VERSION 5.7 ;
BUSBITCHARS "[]" ;
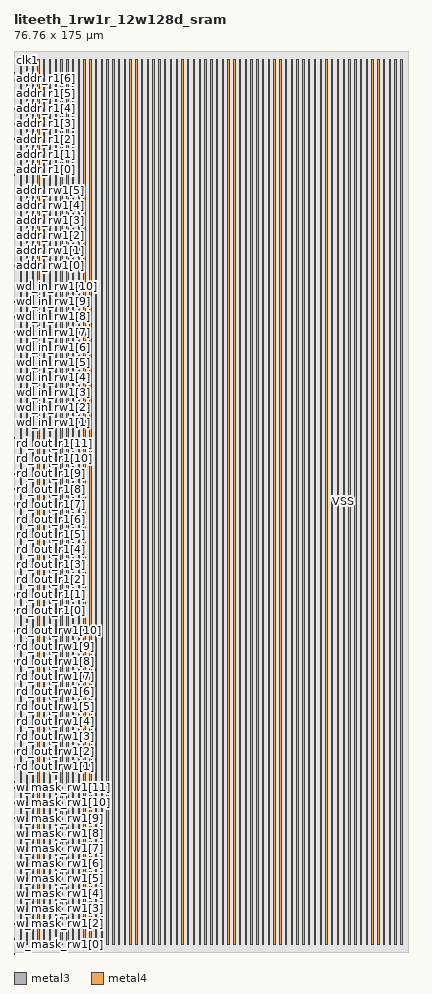
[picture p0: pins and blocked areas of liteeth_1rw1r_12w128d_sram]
MACRO liteeth_1rw1r_12w128d_sram
  FOREIGN liteeth_1rw1r_12w128d_sram 0 0 ;
  SYMMETRY X Y R90 ;
  SIZE 76.760 BY 175.000 ;
  CLASS BLOCK ;
  PIN w_mask_rw1[0]
    DIRECTION INPUT ;
    USE SIGNAL ;
    SHAPE ABUTMENT ;
    PORT
      LAYER metal3 ;
      RECT 0.000 -0.455 0.070 -0.385 ;
    END
  END w_mask_rw1[0]
  PIN w_mask_rw1[1]
    DIRECTION INPUT ;
    USE SIGNAL ;
    SHAPE ABUTMENT ;
    PORT
      LAYER metal3 ;
      RECT 0.000 2.485 0.070 2.555 ;
    END
  END w_mask_rw1[1]
  PIN w_mask_rw1[2]
    DIRECTION INPUT ;
    USE SIGNAL ;
    SHAPE ABUTMENT ;
    PORT
      LAYER metal3 ;
      RECT 0.000 5.425 0.070 5.495 ;
    END
  END w_mask_rw1[2]
  PIN w_mask_rw1[3]
    DIRECTION INPUT ;
    USE SIGNAL ;
    SHAPE ABUTMENT ;
    PORT
      LAYER metal3 ;
      RECT 0.000 8.365 0.070 8.435 ;
    END
  END w_mask_rw1[3]
  PIN w_mask_rw1[4]
    DIRECTION INPUT ;
    USE SIGNAL ;
    SHAPE ABUTMENT ;
    PORT
      LAYER metal3 ;
      RECT 0.000 11.305 0.070 11.375 ;
    END
  END w_mask_rw1[4]
  PIN w_mask_rw1[5]
    DIRECTION INPUT ;
    USE SIGNAL ;
    SHAPE ABUTMENT ;
    PORT
      LAYER metal3 ;
      RECT 0.000 14.245 0.070 14.315 ;
    END
  END w_mask_rw1[5]
  PIN w_mask_rw1[6]
    DIRECTION INPUT ;
    USE SIGNAL ;
    SHAPE ABUTMENT ;
    PORT
      LAYER metal3 ;
      RECT 0.000 17.185 0.070 17.255 ;
    END
  END w_mask_rw1[6]
  PIN w_mask_rw1[7]
    DIRECTION INPUT ;
    USE SIGNAL ;
    SHAPE ABUTMENT ;
    PORT
      LAYER metal3 ;
      RECT 0.000 20.125 0.070 20.195 ;
    END
  END w_mask_rw1[7]
  PIN w_mask_rw1[8]
    DIRECTION INPUT ;
    USE SIGNAL ;
    SHAPE ABUTMENT ;
    PORT
      LAYER metal3 ;
      RECT 0.000 23.065 0.070 23.135 ;
    END
  END w_mask_rw1[8]
  PIN w_mask_rw1[9]
    DIRECTION INPUT ;
    USE SIGNAL ;
    SHAPE ABUTMENT ;
    PORT
      LAYER metal3 ;
      RECT 0.000 26.005 0.070 26.075 ;
    END
  END w_mask_rw1[9]
  PIN w_mask_rw1[10]
    DIRECTION INPUT ;
    USE SIGNAL ;
    SHAPE ABUTMENT ;
    PORT
      LAYER metal3 ;
      RECT 0.000 28.945 0.070 29.015 ;
    END
  END w_mask_rw1[10]
  PIN w_mask_rw1[11]
    DIRECTION INPUT ;
    USE SIGNAL ;
    SHAPE ABUTMENT ;
    PORT
      LAYER metal3 ;
      RECT 0.000 31.885 0.070 31.955 ;
    END
  END w_mask_rw1[11]
  PIN rd_out_rw1[0]
    DIRECTION OUTPUT ;
    USE SIGNAL ;
    SHAPE ABUTMENT ;
    PORT
      LAYER metal3 ;
      RECT 0.000 33.005 0.070 33.075 ;
    END
  END rd_out_rw1[0]
  PIN rd_out_rw1[1]
    DIRECTION OUTPUT ;
    USE SIGNAL ;
    SHAPE ABUTMENT ;
    PORT
      LAYER metal3 ;
      RECT 0.000 35.945 0.070 36.015 ;
    END
  END rd_out_rw1[1]
  PIN rd_out_rw1[2]
    DIRECTION OUTPUT ;
    USE SIGNAL ;
    SHAPE ABUTMENT ;
    PORT
      LAYER metal3 ;
      RECT 0.000 38.885 0.070 38.955 ;
    END
  END rd_out_rw1[2]
  PIN rd_out_rw1[3]
    DIRECTION OUTPUT ;
    USE SIGNAL ;
    SHAPE ABUTMENT ;
    PORT
      LAYER metal3 ;
      RECT 0.000 41.825 0.070 41.895 ;
    END
  END rd_out_rw1[3]
  PIN rd_out_rw1[4]
    DIRECTION OUTPUT ;
    USE SIGNAL ;
    SHAPE ABUTMENT ;
    PORT
      LAYER metal3 ;
      RECT 0.000 44.765 0.070 44.835 ;
    END
  END rd_out_rw1[4]
  PIN rd_out_rw1[5]
    DIRECTION OUTPUT ;
    USE SIGNAL ;
    SHAPE ABUTMENT ;
    PORT
      LAYER metal3 ;
      RECT 0.000 47.705 0.070 47.775 ;
    END
  END rd_out_rw1[5]
  PIN rd_out_rw1[6]
    DIRECTION OUTPUT ;
    USE SIGNAL ;
    SHAPE ABUTMENT ;
    PORT
      LAYER metal3 ;
      RECT 0.000 50.645 0.070 50.715 ;
    END
  END rd_out_rw1[6]
  PIN rd_out_rw1[7]
    DIRECTION OUTPUT ;
    USE SIGNAL ;
    SHAPE ABUTMENT ;
    PORT
      LAYER metal3 ;
      RECT 0.000 53.585 0.070 53.655 ;
    END
  END rd_out_rw1[7]
  PIN rd_out_rw1[8]
    DIRECTION OUTPUT ;
    USE SIGNAL ;
    SHAPE ABUTMENT ;
    PORT
      LAYER metal3 ;
      RECT 0.000 56.525 0.070 56.595 ;
    END
  END rd_out_rw1[8]
  PIN rd_out_rw1[9]
    DIRECTION OUTPUT ;
    USE SIGNAL ;
    SHAPE ABUTMENT ;
    PORT
      LAYER metal3 ;
      RECT 0.000 59.465 0.070 59.535 ;
    END
  END rd_out_rw1[9]
  PIN rd_out_rw1[10]
    DIRECTION OUTPUT ;
    USE SIGNAL ;
    SHAPE ABUTMENT ;
    PORT
      LAYER metal3 ;
      RECT 0.000 62.405 0.070 62.475 ;
    END
  END rd_out_rw1[10]
  PIN rd_out_rw1[11]
    DIRECTION OUTPUT ;
    USE SIGNAL ;
    SHAPE ABUTMENT ;
    PORT
      LAYER metal3 ;
      RECT 0.000 65.345 0.070 65.415 ;
    END
  END rd_out_rw1[11]
  PIN rd_out_r1[0]
    DIRECTION OUTPUT ;
    USE SIGNAL ;
    SHAPE ABUTMENT ;
    PORT
      LAYER metal3 ;
      RECT 0.000 66.465 0.070 66.535 ;
    END
  END rd_out_r1[0]
  PIN rd_out_r1[1]
    DIRECTION OUTPUT ;
    USE SIGNAL ;
    SHAPE ABUTMENT ;
    PORT
      LAYER metal3 ;
      RECT 0.000 69.405 0.070 69.475 ;
    END
  END rd_out_r1[1]
  PIN rd_out_r1[2]
    DIRECTION OUTPUT ;
    USE SIGNAL ;
    SHAPE ABUTMENT ;
    PORT
      LAYER metal3 ;
      RECT 0.000 72.345 0.070 72.415 ;
    END
  END rd_out_r1[2]
  PIN rd_out_r1[3]
    DIRECTION OUTPUT ;
    USE SIGNAL ;
    SHAPE ABUTMENT ;
    PORT
      LAYER metal3 ;
      RECT 0.000 75.285 0.070 75.355 ;
    END
  END rd_out_r1[3]
  PIN rd_out_r1[4]
    DIRECTION OUTPUT ;
    USE SIGNAL ;
    SHAPE ABUTMENT ;
    PORT
      LAYER metal3 ;
      RECT 0.000 78.225 0.070 78.295 ;
    END
  END rd_out_r1[4]
  PIN rd_out_r1[5]
    DIRECTION OUTPUT ;
    USE SIGNAL ;
    SHAPE ABUTMENT ;
    PORT
      LAYER metal3 ;
      RECT 0.000 81.165 0.070 81.235 ;
    END
  END rd_out_r1[5]
  PIN rd_out_r1[6]
    DIRECTION OUTPUT ;
    USE SIGNAL ;
    SHAPE ABUTMENT ;
    PORT
      LAYER metal3 ;
      RECT 0.000 84.105 0.070 84.175 ;
    END
  END rd_out_r1[6]
  PIN rd_out_r1[7]
    DIRECTION OUTPUT ;
    USE SIGNAL ;
    SHAPE ABUTMENT ;
    PORT
      LAYER metal3 ;
      RECT 0.000 87.045 0.070 87.115 ;
    END
  END rd_out_r1[7]
  PIN rd_out_r1[8]
    DIRECTION OUTPUT ;
    USE SIGNAL ;
    SHAPE ABUTMENT ;
    PORT
      LAYER metal3 ;
      RECT 0.000 89.985 0.070 90.055 ;
    END
  END rd_out_r1[8]
  PIN rd_out_r1[9]
    DIRECTION OUTPUT ;
    USE SIGNAL ;
    SHAPE ABUTMENT ;
    PORT
      LAYER metal3 ;
      RECT 0.000 92.925 0.070 92.995 ;
    END
  END rd_out_r1[9]
  PIN rd_out_r1[10]
    DIRECTION OUTPUT ;
    USE SIGNAL ;
    SHAPE ABUTMENT ;
    PORT
      LAYER metal3 ;
      RECT 0.000 95.865 0.070 95.935 ;
    END
  END rd_out_r1[10]
  PIN rd_out_r1[11]
    DIRECTION OUTPUT ;
    USE SIGNAL ;
    SHAPE ABUTMENT ;
    PORT
      LAYER metal3 ;
      RECT 0.000 98.805 0.070 98.875 ;
    END
  END rd_out_r1[11]
  PIN wd_in_rw1[0]
    DIRECTION INPUT ;
    USE SIGNAL ;
    SHAPE ABUTMENT ;
    PORT
      LAYER metal3 ;
      RECT 0.000 99.925 0.070 99.995 ;
    END
  END wd_in_rw1[0]
  PIN wd_in_rw1[1]
    DIRECTION INPUT ;
    USE SIGNAL ;
    SHAPE ABUTMENT ;
    PORT
      LAYER metal3 ;
      RECT 0.000 102.865 0.070 102.935 ;
    END
  END wd_in_rw1[1]
  PIN wd_in_rw1[2]
    DIRECTION INPUT ;
    USE SIGNAL ;
    SHAPE ABUTMENT ;
    PORT
      LAYER metal3 ;
      RECT 0.000 105.805 0.070 105.875 ;
    END
  END wd_in_rw1[2]
  PIN wd_in_rw1[3]
    DIRECTION INPUT ;
    USE SIGNAL ;
    SHAPE ABUTMENT ;
    PORT
      LAYER metal3 ;
      RECT 0.000 108.745 0.070 108.815 ;
    END
  END wd_in_rw1[3]
  PIN wd_in_rw1[4]
    DIRECTION INPUT ;
    USE SIGNAL ;
    SHAPE ABUTMENT ;
    PORT
      LAYER metal3 ;
      RECT 0.000 111.685 0.070 111.755 ;
    END
  END wd_in_rw1[4]
  PIN wd_in_rw1[5]
    DIRECTION INPUT ;
    USE SIGNAL ;
    SHAPE ABUTMENT ;
    PORT
      LAYER metal3 ;
      RECT 0.000 114.625 0.070 114.695 ;
    END
  END wd_in_rw1[5]
  PIN wd_in_rw1[6]
    DIRECTION INPUT ;
    USE SIGNAL ;
    SHAPE ABUTMENT ;
    PORT
      LAYER metal3 ;
      RECT 0.000 117.565 0.070 117.635 ;
    END
  END wd_in_rw1[6]
  PIN wd_in_rw1[7]
    DIRECTION INPUT ;
    USE SIGNAL ;
    SHAPE ABUTMENT ;
    PORT
      LAYER metal3 ;
      RECT 0.000 120.505 0.070 120.575 ;
    END
  END wd_in_rw1[7]
  PIN wd_in_rw1[8]
    DIRECTION INPUT ;
    USE SIGNAL ;
    SHAPE ABUTMENT ;
    PORT
      LAYER metal3 ;
      RECT 0.000 123.445 0.070 123.515 ;
    END
  END wd_in_rw1[8]
  PIN wd_in_rw1[9]
    DIRECTION INPUT ;
    USE SIGNAL ;
    SHAPE ABUTMENT ;
    PORT
      LAYER metal3 ;
      RECT 0.000 126.385 0.070 126.455 ;
    END
  END wd_in_rw1[9]
  PIN wd_in_rw1[10]
    DIRECTION INPUT ;
    USE SIGNAL ;
    SHAPE ABUTMENT ;
    PORT
      LAYER metal3 ;
      RECT 0.000 129.325 0.070 129.395 ;
    END
  END wd_in_rw1[10]
  PIN wd_in_rw1[11]
    DIRECTION INPUT ;
    USE SIGNAL ;
    SHAPE ABUTMENT ;
    PORT
      LAYER metal3 ;
      RECT 0.000 132.265 0.070 132.335 ;
    END
  END wd_in_rw1[11]
  PIN addr_rw1[0]
    DIRECTION INPUT ;
    USE SIGNAL ;
    SHAPE ABUTMENT ;
    PORT
      LAYER metal3 ;
      RECT 0.000 133.385 0.070 133.455 ;
    END
  END addr_rw1[0]
  PIN addr_rw1[1]
    DIRECTION INPUT ;
    USE SIGNAL ;
    SHAPE ABUTMENT ;
    PORT
      LAYER metal3 ;
      RECT 0.000 136.325 0.070 136.395 ;
    END
  END addr_rw1[1]
  PIN addr_rw1[2]
    DIRECTION INPUT ;
    USE SIGNAL ;
    SHAPE ABUTMENT ;
    PORT
      LAYER metal3 ;
      RECT 0.000 139.265 0.070 139.335 ;
    END
  END addr_rw1[2]
  PIN addr_rw1[3]
    DIRECTION INPUT ;
    USE SIGNAL ;
    SHAPE ABUTMENT ;
    PORT
      LAYER metal3 ;
      RECT 0.000 142.205 0.070 142.275 ;
    END
  END addr_rw1[3]
  PIN addr_rw1[4]
    DIRECTION INPUT ;
    USE SIGNAL ;
    SHAPE ABUTMENT ;
    PORT
      LAYER metal3 ;
      RECT 0.000 145.145 0.070 145.215 ;
    END
  END addr_rw1[4]
  PIN addr_rw1[5]
    DIRECTION INPUT ;
    USE SIGNAL ;
    SHAPE ABUTMENT ;
    PORT
      LAYER metal3 ;
      RECT 0.000 148.085 0.070 148.155 ;
    END
  END addr_rw1[5]
  PIN addr_rw1[6]
    DIRECTION INPUT ;
    USE SIGNAL ;
    SHAPE ABUTMENT ;
    PORT
      LAYER metal3 ;
      RECT 0.000 151.025 0.070 151.095 ;
    END
  END addr_rw1[6]
  PIN addr_r1[0]
    DIRECTION INPUT ;
    USE SIGNAL ;
    SHAPE ABUTMENT ;
    PORT
      LAYER metal3 ;
      RECT 0.000 152.145 0.070 152.215 ;
    END
  END addr_r1[0]
  PIN addr_r1[1]
    DIRECTION INPUT ;
    USE SIGNAL ;
    SHAPE ABUTMENT ;
    PORT
      LAYER metal3 ;
      RECT 0.000 155.085 0.070 155.155 ;
    END
  END addr_r1[1]
  PIN addr_r1[2]
    DIRECTION INPUT ;
    USE SIGNAL ;
    SHAPE ABUTMENT ;
    PORT
      LAYER metal3 ;
      RECT 0.000 158.025 0.070 158.095 ;
    END
  END addr_r1[2]
  PIN addr_r1[3]
    DIRECTION INPUT ;
    USE SIGNAL ;
    SHAPE ABUTMENT ;
    PORT
      LAYER metal3 ;
      RECT 0.000 160.965 0.070 161.035 ;
    END
  END addr_r1[3]
  PIN addr_r1[4]
    DIRECTION INPUT ;
    USE SIGNAL ;
    SHAPE ABUTMENT ;
    PORT
      LAYER metal3 ;
      RECT 0.000 163.905 0.070 163.975 ;
    END
  END addr_r1[4]
  PIN addr_r1[5]
    DIRECTION INPUT ;
    USE SIGNAL ;
    SHAPE ABUTMENT ;
    PORT
      LAYER metal3 ;
      RECT 0.000 166.845 0.070 166.915 ;
    END
  END addr_r1[5]
  PIN addr_r1[6]
    DIRECTION INPUT ;
    USE SIGNAL ;
    SHAPE ABUTMENT ;
    PORT
      LAYER metal3 ;
      RECT 0.000 169.785 0.070 169.855 ;
    END
  END addr_r1[6]
  PIN we_in_rw1
    DIRECTION INPUT ;
    USE SIGNAL ;
    SHAPE ABUTMENT ;
    PORT
      LAYER metal3 ;
      RECT 0.000 170.905 0.070 170.975 ;
    END
  END we_in_rw1
  PIN ce_rw1
    DIRECTION INPUT ;
    USE SIGNAL ;
    SHAPE ABUTMENT ;
    PORT
      LAYER metal3 ;
      RECT 0.000 170.205 0.070 170.275 ;
    END
  END ce_rw1
  PIN ce_r1
    DIRECTION INPUT ;
    USE SIGNAL ;
    SHAPE ABUTMENT ;
    PORT
      LAYER metal3 ;
      RECT 0.000 169.505 0.070 169.575 ;
    END
  END ce_r1
  PIN clk0
    DIRECTION INPUT ;
    USE SIGNAL ;
    SHAPE ABUTMENT ;
    PORT
      LAYER metal3 ;
      RECT 0.000 170.625 0.070 170.695 ;
    END
  END clk0
  PIN clk1
    DIRECTION INPUT ;
    USE SIGNAL ;
    SHAPE ABUTMENT ;
    PORT
      LAYER metal3 ;
      RECT 0.000 173.565 0.070 173.635 ;
    END
  END clk1
  PIN VSS
    DIRECTION INOUT ;
    USE GROUND ;
    PORT
      LAYER metal4 ;
      RECT 1.260 1.400 1.540 173.600 ;
      RECT 3.500 1.400 3.780 173.600 ;
      RECT 5.740 1.400 6.020 173.600 ;
      RECT 7.980 1.400 8.260 173.600 ;
      RECT 10.220 1.400 10.500 173.600 ;
      RECT 12.460 1.400 12.740 173.600 ;
      RECT 14.700 1.400 14.980 173.600 ;
      RECT 16.940 1.400 17.220 173.600 ;
      RECT 19.180 1.400 19.460 173.600 ;
      RECT 21.420 1.400 21.700 173.600 ;
      RECT 23.660 1.400 23.940 173.600 ;
      RECT 25.900 1.400 26.180 173.600 ;
      RECT 28.140 1.400 28.420 173.600 ;
      RECT 30.380 1.400 30.660 173.600 ;
      RECT 32.620 1.400 32.900 173.600 ;
      RECT 34.860 1.400 35.140 173.600 ;
      RECT 37.100 1.400 37.380 173.600 ;
      RECT 39.340 1.400 39.620 173.600 ;
      RECT 41.580 1.400 41.860 173.600 ;
      RECT 43.820 1.400 44.100 173.600 ;
      RECT 46.060 1.400 46.340 173.600 ;
      RECT 48.300 1.400 48.580 173.600 ;
      RECT 50.540 1.400 50.820 173.600 ;
      RECT 52.780 1.400 53.060 173.600 ;
      RECT 55.020 1.400 55.300 173.600 ;
      RECT 57.260 1.400 57.540 173.600 ;
      RECT 59.500 1.400 59.780 173.600 ;
      RECT 61.740 1.400 62.020 173.600 ;
      RECT 63.980 1.400 64.260 173.600 ;
      RECT 66.220 1.400 66.500 173.600 ;
      RECT 68.460 1.400 68.740 173.600 ;
      RECT 70.700 1.400 70.980 173.600 ;
      RECT 72.940 1.400 73.220 173.600 ;
      RECT 75.180 1.400 75.460 173.600 ;
    END
  END VSS
  PIN VDD
    DIRECTION INOUT ;
    USE POWER ;
    PORT
      LAYER metal4 ;
      RECT 2.380 1.400 2.660 173.600 ;
      RECT 4.620 1.400 4.900 173.600 ;
      RECT 6.860 1.400 7.140 173.600 ;
      RECT 9.100 1.400 9.380 173.600 ;
      RECT 11.340 1.400 11.620 173.600 ;
      RECT 13.580 1.400 13.860 173.600 ;
      RECT 15.820 1.400 16.100 173.600 ;
      RECT 18.060 1.400 18.340 173.600 ;
      RECT 20.300 1.400 20.580 173.600 ;
      RECT 22.540 1.400 22.820 173.600 ;
      RECT 24.780 1.400 25.060 173.600 ;
      RECT 27.020 1.400 27.300 173.600 ;
      RECT 29.260 1.400 29.540 173.600 ;
      RECT 31.500 1.400 31.780 173.600 ;
      RECT 33.740 1.400 34.020 173.600 ;
      RECT 35.980 1.400 36.260 173.600 ;
      RECT 38.220 1.400 38.500 173.600 ;
      RECT 40.460 1.400 40.740 173.600 ;
      RECT 42.700 1.400 42.980 173.600 ;
      RECT 44.940 1.400 45.220 173.600 ;
      RECT 47.180 1.400 47.460 173.600 ;
      RECT 49.420 1.400 49.700 173.600 ;
      RECT 51.660 1.400 51.940 173.600 ;
      RECT 53.900 1.400 54.180 173.600 ;
      RECT 56.140 1.400 56.420 173.600 ;
      RECT 58.380 1.400 58.660 173.600 ;
      RECT 60.620 1.400 60.900 173.600 ;
      RECT 62.860 1.400 63.140 173.600 ;
      RECT 65.100 1.400 65.380 173.600 ;
      RECT 67.340 1.400 67.620 173.600 ;
      RECT 69.580 1.400 69.860 173.600 ;
      RECT 71.820 1.400 72.100 173.600 ;
      RECT 74.060 1.400 74.340 173.600 ;
    END
  END VDD
  OBS
    LAYER metal1 ;
    RECT 0 0 76.760 175.000 ;
    LAYER metal2 ;
    RECT 0 0 76.760 175.000 ;
    LAYER metal3 ;
    RECT 0.070 0 76.760 175.000 ;
    RECT 0 0.000 0.070 1.365 ;
    RECT 0 1.435 0.070 4.305 ;
    RECT 0 4.375 0.070 7.245 ;
    RECT 0 7.315 0.070 10.185 ;
    RECT 0 10.255 0.070 13.125 ;
    RECT 0 13.195 0.070 16.065 ;
    RECT 0 16.135 0.070 19.005 ;
    RECT 0 19.075 0.070 21.945 ;
    RECT 0 22.015 0.070 24.885 ;
    RECT 0 24.955 0.070 27.825 ;
    RECT 0 27.895 0.070 30.765 ;
    RECT 0 30.835 0.070 33.705 ;
    RECT 0 33.775 0.070 34.825 ;
    RECT 0 34.895 0.070 37.765 ;
    RECT 0 37.835 0.070 40.705 ;
    RECT 0 40.775 0.070 43.645 ;
    RECT 0 43.715 0.070 46.585 ;
    RECT 0 46.655 0.070 49.525 ;
    RECT 0 49.595 0.070 52.465 ;
    RECT 0 52.535 0.070 55.405 ;
    RECT 0 55.475 0.070 58.345 ;
    RECT 0 58.415 0.070 61.285 ;
    RECT 0 61.355 0.070 64.225 ;
    RECT 0 64.295 0.070 67.165 ;
    RECT 0 67.235 0.070 68.285 ;
    RECT 0 68.355 0.070 71.225 ;
    RECT 0 71.295 0.070 74.165 ;
    RECT 0 74.235 0.070 77.105 ;
    RECT 0 77.175 0.070 80.045 ;
    RECT 0 80.115 0.070 82.985 ;
    RECT 0 83.055 0.070 85.925 ;
    RECT 0 85.995 0.070 88.865 ;
    RECT 0 88.935 0.070 91.805 ;
    RECT 0 91.875 0.070 94.745 ;
    RECT 0 94.815 0.070 97.685 ;
    RECT 0 97.755 0.070 100.625 ;
    RECT 0 100.695 0.070 101.745 ;
    RECT 0 101.815 0.070 104.685 ;
    RECT 0 104.755 0.070 107.625 ;
    RECT 0 107.695 0.070 110.565 ;
    RECT 0 110.635 0.070 113.505 ;
    RECT 0 113.575 0.070 116.445 ;
    RECT 0 116.515 0.070 119.385 ;
    RECT 0 119.455 0.070 120.505 ;
    RECT 0 120.575 0.070 123.445 ;
    RECT 0 123.515 0.070 126.385 ;
    RECT 0 126.455 0.070 175.000 ;
    LAYER metal4 ;
    RECT 0 0 76.760 1.400 ;
    RECT 0 173.600 76.760 175.000 ;
    RECT 0.000 1.400 1.260 173.600 ;
    RECT 1.540 1.400 2.380 173.600 ;
    RECT 2.660 1.400 3.500 173.600 ;
    RECT 3.780 1.400 4.620 173.600 ;
    RECT 4.900 1.400 5.740 173.600 ;
    RECT 6.020 1.400 6.860 173.600 ;
    RECT 7.140 1.400 7.980 173.600 ;
    RECT 8.260 1.400 9.100 173.600 ;
    RECT 9.380 1.400 10.220 173.600 ;
    RECT 10.500 1.400 11.340 173.600 ;
    RECT 11.620 1.400 12.460 173.600 ;
    RECT 12.740 1.400 13.580 173.600 ;
    RECT 13.860 1.400 14.700 173.600 ;
    RECT 14.980 1.400 15.820 173.600 ;
    RECT 16.100 1.400 16.940 173.600 ;
    RECT 17.220 1.400 18.060 173.600 ;
    RECT 18.340 1.400 19.180 173.600 ;
    RECT 19.460 1.400 20.300 173.600 ;
    RECT 20.580 1.400 21.420 173.600 ;
    RECT 21.700 1.400 22.540 173.600 ;
    RECT 22.820 1.400 23.660 173.600 ;
    RECT 23.940 1.400 24.780 173.600 ;
    RECT 25.060 1.400 25.900 173.600 ;
    RECT 26.180 1.400 27.020 173.600 ;
    RECT 27.300 1.400 28.140 173.600 ;
    RECT 28.420 1.400 29.260 173.600 ;
    RECT 29.540 1.400 30.380 173.600 ;
    RECT 30.660 1.400 31.500 173.600 ;
    RECT 31.780 1.400 32.620 173.600 ;
    RECT 32.900 1.400 33.740 173.600 ;
    RECT 34.020 1.400 34.860 173.600 ;
    RECT 35.140 1.400 35.980 173.600 ;
    RECT 36.260 1.400 37.100 173.600 ;
    RECT 37.380 1.400 38.220 173.600 ;
    RECT 38.500 1.400 39.340 173.600 ;
    RECT 39.620 1.400 40.460 173.600 ;
    RECT 40.740 1.400 41.580 173.600 ;
    RECT 41.860 1.400 42.700 173.600 ;
    RECT 42.980 1.400 43.820 173.600 ;
    RECT 44.100 1.400 44.940 173.600 ;
    RECT 45.220 1.400 46.060 173.600 ;
    RECT 46.340 1.400 47.180 173.600 ;
    RECT 47.460 1.400 48.300 173.600 ;
    RECT 48.580 1.400 49.420 173.600 ;
    RECT 49.700 1.400 50.540 173.600 ;
    RECT 50.820 1.400 51.660 173.600 ;
    RECT 51.940 1.400 52.780 173.600 ;
    RECT 53.060 1.400 53.900 173.600 ;
    RECT 54.180 1.400 55.020 173.600 ;
    RECT 55.300 1.400 56.140 173.600 ;
    RECT 56.420 1.400 57.260 173.600 ;
    RECT 57.540 1.400 58.380 173.600 ;
    RECT 58.660 1.400 59.500 173.600 ;
    RECT 59.780 1.400 60.620 173.600 ;
    RECT 60.900 1.400 61.740 173.600 ;
    RECT 62.020 1.400 62.860 173.600 ;
    RECT 63.140 1.400 63.980 173.600 ;
    RECT 64.260 1.400 65.100 173.600 ;
    RECT 65.380 1.400 66.220 173.600 ;
    RECT 66.500 1.400 67.340 173.600 ;
    RECT 67.620 1.400 68.460 173.600 ;
    RECT 68.740 1.400 69.580 173.600 ;
    RECT 69.860 1.400 70.700 173.600 ;
    RECT 70.980 1.400 71.820 173.600 ;
    RECT 72.100 1.400 72.940 173.600 ;
    RECT 73.220 1.400 74.060 173.600 ;
    RECT 74.340 1.400 75.180 173.600 ;
    RECT 75.460 1.400 76.760 173.600 ;
    LAYER OVERLAP ;
    RECT 0 0 76.760 175.000 ;
  END
END liteeth_1rw1r_12w128d_sram

END LIBRARY
